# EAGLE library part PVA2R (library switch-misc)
ITT SWITCH

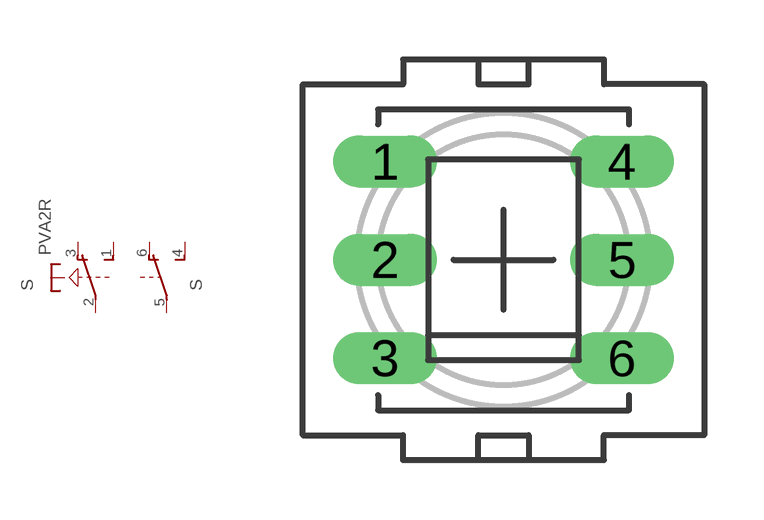
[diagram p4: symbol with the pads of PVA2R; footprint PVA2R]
Designator prefix S; gates 1=TRSU- 2=U-2

## PVA2R  [PVA2R]
1  1:S  pas
2  1:P  pas
3  1:O  pas
4  2:S  pas
5  2:P  pas
6  2:O  pas

## Footprint PVA2R (pad centres in mm)
ITT SWITCH
drill 0.813 long: 1 -2.997,2.489; 2 -2.997,0; 3 -2.997,-2.489; 4 2.997,2.489; 5 2.997,0; 6 2.997,-2.489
